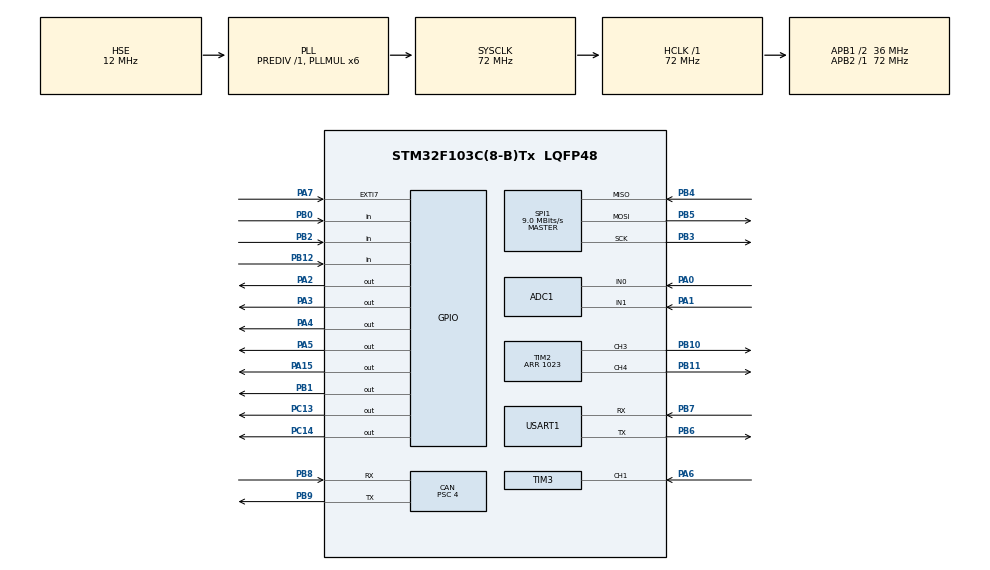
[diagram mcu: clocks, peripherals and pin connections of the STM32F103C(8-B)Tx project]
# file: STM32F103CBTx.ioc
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ADC1.Channel-0\#ChannelRegularConversion=ADC_CHANNEL_0
ADC1.Channel-1\#ChannelRegularConversion=ADC_CHANNEL_1
ADC1.ContinuousConvMode=ENABLE
ADC1.NbrOfConversion=2
ADC1.NbrOfConversionFlag=1
ADC1.Rank-0\#ChannelRegularConversion=1
ADC1.Rank-1\#ChannelRegularConversion=2
ADC1.SamplingTime-0\#ChannelRegularConversion=ADC_SAMPLETIME_239CYCLES_5
ADC1.SamplingTime-1\#ChannelRegularConversion=ADC_SAMPLETIME_1CYCLE_5
ADC1.master=1
CAN.AWUM=ENABLE
CAN.BS1=CAN_BS1_5TQ
CAN.BS2=CAN_BS2_3TQ
CAN.CalculateBaudRate=1000000
CAN.CalculateTimeBit=1000
CAN.CalculateTimeQuantum=111.11111111111111
CAN.Prescaler=4
Dma.ADC1.0.Direction=DMA_PERIPH_TO_MEMORY
Dma.ADC1.0.Instance=DMA1_Channel1
Dma.ADC1.0.MemDataAlignment=DMA_MDATAALIGN_HALFWORD
Dma.ADC1.0.MemInc=DMA_MINC_ENABLE
Dma.ADC1.0.Mode=DMA_CIRCULAR
Dma.ADC1.0.PeriphDataAlignment=DMA_PDATAALIGN_HALFWORD
Dma.ADC1.0.PeriphInc=DMA_PINC_DISABLE
Dma.ADC1.0.Priority=DMA_PRIORITY_VERY_HIGH
Dma.Request0=ADC1
Dma.Request1=USART1_RX
Dma.Request2=USART1_TX
Dma.USART1_RX.1.Direction=DMA_PERIPH_TO_MEMORY
Dma.USART1_RX.1.Instance=DMA1_Channel5
Dma.USART1_RX.1.MemDataAlignment=DMA_MDATAALIGN_BYTE
Dma.USART1_RX.1.MemInc=DMA_MINC_ENABLE
Dma.USART1_RX.1.Mode=DMA_NORMAL
Dma.USART1_RX.1.PeriphDataAlignment=DMA_PDATAALIGN_BYTE
Dma.USART1_RX.1.PeriphInc=DMA_PINC_DISABLE
Dma.USART1_RX.1.Priority=DMA_PRIORITY_MEDIUM
Dma.USART1_TX.2.Direction=DMA_MEMORY_TO_PERIPH
Dma.USART1_TX.2.Instance=DMA1_Channel4
Dma.USART1_TX.2.MemDataAlignment=DMA_MDATAALIGN_BYTE
Dma.USART1_TX.2.MemInc=DMA_MINC_ENABLE
Dma.USART1_TX.2.Mode=DMA_NORMAL
Dma.USART1_TX.2.PeriphDataAlignment=DMA_PDATAALIGN_BYTE
Dma.USART1_TX.2.PeriphInc=DMA_PINC_DISABLE
Dma.USART1_TX.2.Priority=DMA_PRIORITY_MEDIUM
Mcu.Family=STM32F1
Mcu.Name=STM32F103C(8-B)Tx
Mcu.Package=LQFP48
NVIC.CAN1_RX1_IRQn=true\:3\:0\:true\:false\:true\:true\:true\:true
NVIC.CAN1_SCE_IRQn=true\:3\:0\:true\:false\:true\:true\:true\:true
NVIC.DMA1_Channel1_IRQn=true\:0\:0\:false\:false\:true\:false\:true\:true
NVIC.DMA1_Channel4_IRQn=true\:3\:0\:true\:false\:true\:false\:true\:true
NVIC.DMA1_Channel5_IRQn=true\:3\:0\:true\:false\:true\:false\:true\:true
NVIC.EXTI9_5_IRQn=true\:0\:0\:false\:false\:true\:true\:true\:true
NVIC.PriorityGroup=NVIC_PRIORITYGROUP_4
NVIC.TIM1_UP_IRQn=true\:5\:0\:true\:false\:true\:true\:true\:true
NVIC.TIM3_IRQn=true\:0\:0\:false\:false\:true\:true\:true\:true
NVIC.TIM4_IRQn=true\:0\:0\:false\:false\:true\:true\:true\:true
NVIC.USART1_IRQn=true\:3\:0\:true\:false\:true\:true\:true\:true
NVIC.USB_HP_CAN1_TX_IRQn=true\:3\:0\:true\:false\:true\:true\:true\:true
NVIC.USB_LP_CAN1_RX0_IRQn=true\:3\:0\:true\:false\:true\:true\:true\:true
PA0-WKUP.Signal=ADCx_IN0
PA1.Signal=ADCx_IN1
PA15.Signal=GPIO_Output
PA2.GPIO_Speed=GPIO_SPEED_FREQ_HIGH
PA2.Signal=GPIO_Output
PA3.GPIO_Speed=GPIO_SPEED_FREQ_HIGH
PA3.Signal=GPIO_Output
PA4.GPIO_Speed=GPIO_SPEED_FREQ_HIGH
PA4.Signal=GPIO_Output
PA5.GPIO_Speed=GPIO_SPEED_FREQ_HIGH
PA5.Signal=GPIO_Output
PA6.Signal=S_TIM3_CH1
PA7.GPIO_ModeDefaultEXTI=GPIO_MODE_IT_RISING_FALLING
PA7.Signal=GPXTI7
PB0.Signal=GPIO_Input
PB1.Signal=GPIO_Output
PB10.GPIO_Speed=GPIO_SPEED_FREQ_HIGH
PB10.Signal=S_TIM2_CH3
PB11.GPIO_Speed=GPIO_SPEED_FREQ_HIGH
PB11.Signal=S_TIM2_CH4
PB12.GPIO_PuPd=GPIO_PULLUP
PB12.Signal=GPIO_Input
PB2.GPIO_PuPd=GPIO_PULLUP
PB2.Signal=GPIO_Input
PB3.Mode=Full_Duplex_Master
PB3.Signal=SPI1_SCK
PB4.Mode=Full_Duplex_Master
PB4.Signal=SPI1_MISO
PB5.Mode=Full_Duplex_Master
PB5.Signal=SPI1_MOSI
PB6.Mode=Asynchronous
PB6.Signal=USART1_TX
PB7.Mode=Asynchronous
PB7.Signal=USART1_RX
PB8.Mode=CAN_Activate
PB8.Signal=CAN_RX
PB9.Mode=CAN_Activate
PB9.Signal=CAN_TX
PC13-TAMPER-RTC.Signal=GPIO_Output
PC14-OSC32_IN.Signal=GPIO_Output
PD0-OSC_IN.Mode=HSE-External-Oscillator
PD0-OSC_IN.Signal=RCC_OSC_IN
PD1-OSC_OUT.Mode=HSE-External-Oscillator
PD1-OSC_OUT.Signal=RCC_OSC_OUT
ProjectManager.HeapSize=0x200
ProjectManager.StackSize=0x400
ProjectManager.TargetToolchain=STM32CubeIDE
RCC.ADCPresc=RCC_ADCPCLK2_DIV6
RCC.AHBFreq_Value=72000000
RCC.APB1CLKDivider=RCC_HCLK_DIV2
RCC.APB1Freq_Value=36000000
RCC.APB1TimFreq_Value=72000000
RCC.APB2Freq_Value=72000000
RCC.APB2TimFreq_Value=72000000
RCC.HCLKFreq_Value=72000000
RCC.HSE_VALUE=12000000
RCC.PLLMUL=RCC_PLL_MUL6
RCC.PLLSourceVirtual=RCC_PLLSOURCE_HSE
RCC.SYSCLKFreq_VALUE=72000000
RCC.SYSCLKSource=RCC_SYSCLKSOURCE_PLLCLK
RCC.USBFreq_Value=72000000
SH.ADCx_IN0.0=ADC1_IN0,IN0
SH.ADCx_IN1.0=ADC1_IN1,IN1
SH.S_TIM2_CH3.0=TIM2_CH3,PWM Generation3 CH3
SH.S_TIM2_CH4.0=TIM2_CH4,PWM Generation4 CH4
SH.S_TIM3_CH1.0=TIM3_CH1,TriggerSource_TI1FP1
SH.S_TIM3_CH1.1=TIM3_CH1,Input_Capture1_from_TI1
SPI1.BaudRatePrescaler=SPI_BAUDRATEPRESCALER_8
SPI1.CLKPhase=SPI_PHASE_2EDGE
SPI1.CLKPolarity=SPI_POLARITY_HIGH
SPI1.CRCCalculation=SPI_CRCCALCULATION_DISABLE
SPI1.CalculateBaudRate=9.0 MBits/s
SPI1.DataSize=SPI_DATASIZE_16BIT
SPI1.Direction=SPI_DIRECTION_2LINES
SPI1.Mode=SPI_MODE_MASTER
SPI1.VirtualType=VM_MASTER
TIM1.AutoReloadPreload=TIM_AUTORELOAD_PRELOAD_ENABLE
TIM1.ClockDivision=TIM_CLOCKDIVISION_DIV1
TIM1.Period=9999
TIM1.Prescaler=71
TIM2.Channel-PWM\ Generation3\ CH3=TIM_CHANNEL_3
TIM2.Channel-PWM\ Generation4\ CH4=TIM_CHANNEL_4
TIM2.ClockDivision=TIM_CLOCKDIVISION_DIV1
TIM2.Period=1023
TIM3.Channel-Input_Capture1_from_TI1=TIM_CHANNEL_1
TIM3.ClockDivision=TIM_CLOCKDIVISION_DIV1
TIM3.ICPrescaler-Input_Capture1_from_TI1=TIM_ICPSC_DIV2
TIM3.Prescaler=71
TIM4.AutoReloadPreload=TIM_AUTORELOAD_PRELOAD_ENABLE
TIM4.ClockDivision=TIM_CLOCKDIVISION_DIV1
TIM4.Period=49
TIM4.Prescaler=71
USART1.VirtualMode=VM_ASYNC
VP_SYS_VS_ND.Mode=No_Debug
VP_TIM1_VS_ClockSourceINT.Mode=Internal
VP_TIM3_VS_ControllerModeReset.Mode=Reset Mode
VP_TIM4_VS_ClockSourceINT.Mode=Internal
board=custom

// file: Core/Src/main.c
/* USER CODE BEGIN Header */
/**
  ******************************************************************************
  * @file           : main.c
  * @brief          : Main program body
  ******************************************************************************
  * @attention
  *
  * Copyright (c) 2024 STMicroelectronics.
  * All rights reserved.
  *
  * This software is licensed under terms that can be found in the LICENSE file
  * in the root directory of this software component.
  * If no LICENSE file comes with this software, it is provided AS-IS.
  *
  ******************************************************************************
  */
/* USER CODE END Header */
#include "main.h"

/* USER CODE BEGIN Includes */
#include "common_inc.h"
#include "configurations.h"
/* USER CODE END Includes */

/* USER CODE BEGIN PD */
uint16_t whole_adc_data[2][12];
/* USER CODE END PD */

 ADC_HandleTypeDef hadc1;
DMA_HandleTypeDef hdma_adc1;

CAN_HandleTypeDef hcan;

SPI_HandleTypeDef hspi1;

TIM_HandleTypeDef htim1;
TIM_HandleTypeDef htim2;
TIM_HandleTypeDef htim3;
TIM_HandleTypeDef htim4;

UART_HandleTypeDef huart1;
DMA_HandleTypeDef hdma_usart1_rx;
DMA_HandleTypeDef hdma_usart1_tx;

/* USER CODE BEGIN PV */
CAN_TxHeaderTypeDef TxHeader;
CAN_RxHeaderTypeDef RxHeader;
uint8_t TxData[8];
uint8_t RxData[8];
uint32_t TxMailbox;
/* USER CODE END PV */

void SystemClock_Config(void);
static void MX_GPIO_Init(void);
static void MX_DMA_Init(void);
static void MX_ADC1_Init(void);
static void MX_CAN_Init(void);
static void MX_SPI1_Init(void);
static void MX_TIM1_Init(void);
static void MX_TIM2_Init(void);
static void MX_TIM3_Init(void);
static void MX_TIM4_Init(void);
static void MX_USART1_UART_Init(void);

/* USER CODE BEGIN 0 */
void CAN_Send(CAN_TxHeaderTypeDef* pHeader, uint8_t* data)
{
    if (HAL_CAN_AddTxMessage(&hcan, pHeader, data, &TxMailbox) != HAL_OK)
    {
        Error_Handler();
    }
}

void HAL_CAN_RxFifo0MsgPendingCallback(CAN_HandleTypeDef* CanHandle)
{
    /* Get RX message */
    if (HAL_CAN_GetRxMessage(CanHandle, CAN_RX_FIFO0, &RxHeader, RxData) != HAL_OK)
    {
        /* Reception Error */
        Error_Handler();
    }

    uint8_t id = (RxHeader.StdId >> 7); // 4Bits ID & 7Bits Msg
    uint8_t cmd = RxHeader.StdId & 0x7F; // 4Bits ID & 7Bits Msg
    if (id == 0 || id == boardConfig.canNodeId)
    {
        OnCanCmd(cmd, RxData, RxHeader.DLC);
    }
}
/* USER CODE END 0 */

int main(void)
{

  /* MCU Configuration--------------------------------------------------------*/

  /* Reset of all peripherals, Initializes the Flash interface and the Systick. */
  HAL_Init();

  /* Configure the system clock */
  SystemClock_Config();

  /* Initialize all configured peripherals */
  MX_GPIO_Init();
  MX_DMA_Init();
  MX_ADC1_Init();
  MX_CAN_Init();
  MX_SPI1_Init();
  MX_TIM1_Init();
  MX_TIM2_Init();
  MX_TIM3_Init();
  MX_TIM4_Init();
  MX_USART1_UART_Init();
  /* USER CODE BEGIN 2 */
  Main();
  /* USER CODE END 2 */

  /* Infinite loop */
  while (1)
  {

  }
}

void SystemClock_Config(void)
{
  RCC_OscInitTypeDef RCC_OscInitStruct = {0};
  RCC_ClkInitTypeDef RCC_ClkInitStruct = {0};
  RCC_PeriphCLKInitTypeDef PeriphClkInit = {0};

  /** Initializes the RCC Oscillators according to the specified parameters
  * in the RCC_OscInitTypeDef structure.
  */
  RCC_OscInitStruct.OscillatorType = RCC_OSCILLATORTYPE_HSE;
  RCC_OscInitStruct.HSEState = RCC_HSE_ON;
  RCC_OscInitStruct.HSEPredivValue = RCC_HSE_PREDIV_DIV1;
  RCC_OscInitStruct.HSIState = RCC_HSI_ON;
  RCC_OscInitStruct.PLL.PLLState = RCC_PLL_ON;
  RCC_OscInitStruct.PLL.PLLSource = RCC_PLLSOURCE_HSE;
  RCC_OscInitStruct.PLL.PLLMUL = RCC_PLL_MUL6;
  if (HAL_RCC_OscConfig(&RCC_OscInitStruct) != HAL_OK)
  {
    Error_Handler();
  }

  /** Initializes the CPU, AHB and APB buses clocks
  */
  RCC_ClkInitStruct.ClockType = RCC_CLOCKTYPE_HCLK|RCC_CLOCKTYPE_SYSCLK
                              |RCC_CLOCKTYPE_PCLK1|RCC_CLOCKTYPE_PCLK2;
  RCC_ClkInitStruct.SYSCLKSource = RCC_SYSCLKSOURCE_PLLCLK;
  RCC_ClkInitStruct.AHBCLKDivider = RCC_SYSCLK_DIV1;
  RCC_ClkInitStruct.APB1CLKDivider = RCC_HCLK_DIV2;
  RCC_ClkInitStruct.APB2CLKDivider = RCC_HCLK_DIV1;

  if (HAL_RCC_ClockConfig(&RCC_ClkInitStruct, FLASH_LATENCY_2) != HAL_OK)
  {
    Error_Handler();
  }
  PeriphClkInit.PeriphClockSelection = RCC_PERIPHCLK_ADC;
  PeriphClkInit.AdcClockSelection = RCC_ADCPCLK2_DIV6;
  if (HAL_RCCEx_PeriphCLKConfig(&PeriphClkInit) != HAL_OK)
  {
    Error_Handler();
  }
}

static void MX_ADC1_Init(void)
{

  ADC_ChannelConfTypeDef sConfig = {0};

  /** Common config
  */
  hadc1.Instance = ADC1;
  hadc1.Init.ScanConvMode = ADC_SCAN_ENABLE;
  hadc1.Init.ContinuousConvMode = ENABLE;
  hadc1.Init.DiscontinuousConvMode = DISABLE;
  hadc1.Init.ExternalTrigConv = ADC_SOFTWARE_START;
  hadc1.Init.DataAlign = ADC_DATAALIGN_RIGHT;
  hadc1.Init.NbrOfConversion = 2;
  if (HAL_ADC_Init(&hadc1) != HAL_OK)
  {
    Error_Handler();
  }

  /** Configure Regular Channel
  */
  sConfig.Channel = ADC_CHANNEL_0;
  sConfig.Rank = ADC_REGULAR_RANK_1;
  sConfig.SamplingTime = ADC_SAMPLETIME_239CYCLES_5;
  if (HAL_ADC_ConfigChannel(&hadc1, &sConfig) != HAL_OK)
  {
    Error_Handler();
  }

  /** Configure Regular Channel
  */
  sConfig.Channel = ADC_CHANNEL_1;
  sConfig.Rank = ADC_REGULAR_RANK_2;
  sConfig.SamplingTime = ADC_SAMPLETIME_1CYCLE_5;
  if (HAL_ADC_ConfigChannel(&hadc1, &sConfig) != HAL_OK)
  {
    Error_Handler();
  }
  /* USER CODE BEGIN ADC1_Init 2 */
  HAL_ADCEx_Calibration_Start(&hadc1);
  HAL_ADC_Start_DMA(&hadc1, (uint32_t*)&whole_adc_data[0][0], 2);
  /* USER CODE END ADC1_Init 2 */

}

static void MX_CAN_Init(void)
{

  hcan.Instance = CAN1;
  hcan.Init.Prescaler = 4;
  hcan.Init.Mode = CAN_MODE_NORMAL;
  hcan.Init.SyncJumpWidth = CAN_SJW_1TQ;
  hcan.Init.TimeSeg1 = CAN_BS1_5TQ;
  hcan.Init.TimeSeg2 = CAN_BS2_3TQ;
  hcan.Init.TimeTriggeredMode = DISABLE;
  hcan.Init.AutoBusOff = DISABLE;
  hcan.Init.AutoWakeUp = ENABLE;
  hcan.Init.AutoRetransmission = DISABLE;
  hcan.Init.ReceiveFifoLocked = DISABLE;
  hcan.Init.TransmitFifoPriority = DISABLE;
  if (HAL_CAN_Init(&hcan) != HAL_OK)
  {
    Error_Handler();
  }
  /* USER CODE BEGIN CAN_Init 2 */
  CAN_FilterTypeDef sFilterConfig;
  //filter one (stack light blink)
  sFilterConfig.FilterBank = 0;
  sFilterConfig.FilterMode = CAN_FILTERMODE_IDMASK;
  sFilterConfig.FilterScale = CAN_FILTERSCALE_32BIT;
  sFilterConfig.FilterIdHigh = 0x0000;
  sFilterConfig.FilterIdLow = 0x0000;
  sFilterConfig.FilterMaskIdHigh = 0x0000;
  sFilterConfig.FilterMaskIdLow = 0x0000;
  sFilterConfig.FilterFIFOAssignment = CAN_RX_FIFO0;
  sFilterConfig.FilterActivation = ENABLE;
  sFilterConfig.SlaveStartFilterBank = 14;
  if (HAL_CAN_ConfigFilter(&hcan, &sFilterConfig) != HAL_OK)
  {
      /* Filter configuration Error */
      Error_Handler();
  }

  HAL_CAN_Start(&hcan); //start CAN

  HAL_CAN_ActivateNotification(&hcan,
                               CAN_IT_TX_MAILBOX_EMPTY |
                               CAN_IT_RX_FIFO0_MSG_PENDING | CAN_IT_RX_FIFO1_MSG_PENDING |
                               /* we probably only want this */
                               CAN_IT_RX_FIFO0_FULL | CAN_IT_RX_FIFO1_FULL |
                               CAN_IT_RX_FIFO0_OVERRUN | CAN_IT_RX_FIFO1_OVERRUN |
                               CAN_IT_WAKEUP | CAN_IT_SLEEP_ACK |
                               CAN_IT_ERROR_WARNING | CAN_IT_ERROR_PASSIVE |
                               CAN_IT_BUSOFF | CAN_IT_LAST_ERROR_CODE |
                               CAN_IT_ERROR);

  /* Configure Transmission process */
  TxHeader.StdId = boardConfig.canNodeId;
  TxHeader.ExtId = 0x00;
  TxHeader.RTR = CAN_RTR_DATA;
  TxHeader.IDE = CAN_ID_STD;
  TxHeader.DLC = 8;
  TxHeader.TransmitGlobalTime = DISABLE;
  /* USER CODE END CAN_Init 2 */

}

static void MX_SPI1_Init(void)
{

  /* SPI1 parameter configuration*/
  hspi1.Instance = SPI1;
  hspi1.Init.Mode = SPI_MODE_MASTER;
  hspi1.Init.Direction = SPI_DIRECTION_2LINES;
  hspi1.Init.DataSize = SPI_DATASIZE_16BIT;
  hspi1.Init.CLKPolarity = SPI_POLARITY_HIGH;
  hspi1.Init.CLKPhase = SPI_PHASE_2EDGE;
  hspi1.Init.NSS = SPI_NSS_SOFT;
  hspi1.Init.BaudRatePrescaler = SPI_BAUDRATEPRESCALER_8;
  hspi1.Init.FirstBit = SPI_FIRSTBIT_MSB;
  hspi1.Init.TIMode = SPI_TIMODE_DISABLE;
  hspi1.Init.CRCCalculation = SPI_CRCCALCULATION_DISABLE;
  hspi1.Init.CRCPolynomial = 10;
  if (HAL_SPI_Init(&hspi1) != HAL_OK)
  {
    Error_Handler();
  }

}

static void MX_TIM1_Init(void)
{

  TIM_ClockConfigTypeDef sClockSourceConfig = {0};
  TIM_MasterConfigTypeDef sMasterConfig = {0};

  htim1.Instance = TIM1;
  htim1.Init.Prescaler = 71;
  htim1.Init.CounterMode = TIM_COUNTERMODE_UP;
  htim1.Init.Period = 9999;
  htim1.Init.ClockDivision = TIM_CLOCKDIVISION_DIV1;
  htim1.Init.RepetitionCounter = 0;
  htim1.Init.AutoReloadPreload = TIM_AUTORELOAD_PRELOAD_ENABLE;
  if (HAL_TIM_Base_Init(&htim1) != HAL_OK)
  {
    Error_Handler();
  }
  sClockSourceConfig.ClockSource = TIM_CLOCKSOURCE_INTERNAL;
  if (HAL_TIM_ConfigClockSource(&htim1, &sClockSourceConfig) != HAL_OK)
  {
    Error_Handler();
  }
  sMasterConfig.MasterOutputTrigger = TIM_TRGO_RESET;
  sMasterConfig.MasterSlaveMode = TIM_MASTERSLAVEMODE_DISABLE;
  if (HAL_TIMEx_MasterConfigSynchronization(&htim1, &sMasterConfig) != HAL_OK)
  {
    Error_Handler();
  }

}

static void MX_TIM2_Init(void)
{

  TIM_MasterConfigTypeDef sMasterConfig = {0};
  TIM_OC_InitTypeDef sConfigOC = {0};

  htim2.Instance = TIM2;
  htim2.Init.Prescaler = 0;
  htim2.Init.CounterMode = TIM_COUNTERMODE_UP;
  htim2.Init.Period = 1023;
  htim2.Init.ClockDivision = TIM_CLOCKDIVISION_DIV1;
  htim2.Init.AutoReloadPreload = TIM_AUTORELOAD_PRELOAD_DISABLE;
  if (HAL_TIM_PWM_Init(&htim2) != HAL_OK)
  {
    Error_Handler();
  }
  sMasterConfig.MasterOutputTrigger = TIM_TRGO_RESET;
  sMasterConfig.MasterSlaveMode = TIM_MASTERSLAVEMODE_DISABLE;
  if (HAL_TIMEx_MasterConfigSynchronization(&htim2, &sMasterConfig) != HAL_OK)
  {
    Error_Handler();
  }
  sConfigOC.OCMode = TIM_OCMODE_PWM1;
  sConfigOC.Pulse = 0;
  sConfigOC.OCPolarity = TIM_OCPOLARITY_HIGH;
  sConfigOC.OCFastMode = TIM_OCFAST_DISABLE;
  if (HAL_TIM_PWM_ConfigChannel(&htim2, &sConfigOC, TIM_CHANNEL_3) != HAL_OK)
  {
    Error_Handler();
  }
  if (HAL_TIM_PWM_ConfigChannel(&htim2, &sConfigOC, TIM_CHANNEL_4) != HAL_OK)
  {
    Error_Handler();
  }
  /* USER CODE BEGIN TIM2_Init 2 */
  HAL_TIM_PWM_Start(&htim2, TIM_CHANNEL_3);
  HAL_TIM_PWM_Start(&htim2, TIM_CHANNEL_4);
  /* USER CODE END TIM2_Init 2 */
  HAL_TIM_MspPostInit(&htim2);

}

static void MX_TIM3_Init(void)
{

  TIM_SlaveConfigTypeDef sSlaveConfig = {0};
  TIM_MasterConfigTypeDef sMasterConfig = {0};
  TIM_IC_InitTypeDef sConfigIC = {0};

  htim3.Instance = TIM3;
  htim3.Init.Prescaler = 71;
  htim3.Init.CounterMode = TIM_COUNTERMODE_UP;
  htim3.Init.Period = 65535;
  htim3.Init.ClockDivision = TIM_CLOCKDIVISION_DIV1;
  htim3.Init.AutoReloadPreload = TIM_AUTORELOAD_PRELOAD_DISABLE;
  if (HAL_TIM_Base_Init(&htim3) != HAL_OK)
  {
    Error_Handler();
  }
  if (HAL_TIM_IC_Init(&htim3) != HAL_OK)
  {
    Error_Handler();
  }
  sSlaveConfig.SlaveMode = TIM_SLAVEMODE_RESET;
  sSlaveConfig.InputTrigger = TIM_TS_TI1FP1;
  sSlaveConfig.TriggerPolarity = TIM_INPUTCHANNELPOLARITY_RISING;
  sSlaveConfig.TriggerFilter = 0;
  if (HAL_TIM_SlaveConfigSynchro(&htim3, &sSlaveConfig) != HAL_OK)
  {
    Error_Handler();
  }
  sMasterConfig.MasterOutputTrigger = TIM_TRGO_RESET;
  sMasterConfig.MasterSlaveMode = TIM_MASTERSLAVEMODE_DISABLE;
  if (HAL_TIMEx_MasterConfigSynchronization(&htim3, &sMasterConfig) != HAL_OK)
  {
    Error_Handler();
  }
  sConfigIC.ICPolarity = TIM_INPUTCHANNELPOLARITY_RISING;
  sConfigIC.ICSelection = TIM_ICSELECTION_DIRECTTI;
  sConfigIC.ICPrescaler = TIM_ICPSC_DIV2;
  sConfigIC.ICFilter = 0;
  if (HAL_TIM_IC_ConfigChannel(&htim3, &sConfigIC, TIM_CHANNEL_1) != HAL_OK)
  {
    Error_Handler();
  }

}

static void MX_TIM4_Init(void)
{

  TIM_ClockConfigTypeDef sClockSourceConfig = {0};
  TIM_MasterConfigTypeDef sMasterConfig = {0};

  htim4.Instance = TIM4;
  htim4.Init.Prescaler = 71;
  htim4.Init.CounterMode = TIM_COUNTERMODE_UP;
  htim4.Init.Period = 49;
  htim4.Init.ClockDivision = TIM_CLOCKDIVISION_DIV1;
  htim4.Init.AutoReloadPreload = TIM_AUTORELOAD_PRELOAD_ENABLE;
  if (HAL_TIM_Base_Init(&htim4) != HAL_OK)
  {
    Error_Handler();
  }
  sClockSourceConfig.ClockSource = TIM_CLOCKSOURCE_INTERNAL;
  if (HAL_TIM_ConfigClockSource(&htim4, &sClockSourceConfig) != HAL_OK)
  {
    Error_Handler();
  }
  sMasterConfig.MasterOutputTrigger = TIM_TRGO_RESET;
  sMasterConfig.MasterSlaveMode = TIM_MASTERSLAVEMODE_DISABLE;
  if (HAL_TIMEx_MasterConfigSynchronization(&htim4, &sMasterConfig) != HAL_OK)
  {
    Error_Handler();
  }

}

static void MX_USART1_UART_Init(void)
{

  huart1.Instance = USART1;
  huart1.Init.BaudRate = 115200;
  huart1.Init.WordLength = UART_WORDLENGTH_8B;
  huart1.Init.StopBits = UART_STOPBITS_1;
  huart1.Init.Parity = UART_PARITY_NONE;
  huart1.Init.Mode = UART_MODE_TX_RX;
  huart1.Init.HwFlowCtl = UART_HWCONTROL_NONE;
  huart1.Init.OverSampling = UART_OVERSAMPLING_16;
  if (HAL_UART_Init(&huart1) != HAL_OK)
  {
    Error_Handler();
  }
  /* USER CODE BEGIN USART1_Init 2 */
  __HAL_UART_ENABLE_IT(&huart1, UART_IT_IDLE);
  RetargetInit(&huart1);
  Uart_SetRxCpltCallBack(OnUartCmd);

  HAL_UART_Receive_DMA(&huart1, rx_buffer, BUFFER_SIZE);
  /* USER CODE END USART1_Init 2 */

}

static void MX_DMA_Init(void)
{

  /* DMA controller clock enable */
  __HAL_RCC_DMA1_CLK_ENABLE();

  /* DMA interrupt init */
  /* DMA1_Channel1_IRQn interrupt configuration */
  HAL_NVIC_SetPriority(DMA1_Channel1_IRQn, 0, 0);
  HAL_NVIC_EnableIRQ(DMA1_Channel1_IRQn);
  /* DMA1_Channel4_IRQn interrupt configuration */
  HAL_NVIC_SetPriority(DMA1_Channel4_IRQn, 3, 0);
  HAL_NVIC_EnableIRQ(DMA1_Channel4_IRQn);
  /* DMA1_Channel5_IRQn interrupt configuration */
  HAL_NVIC_SetPriority(DMA1_Channel5_IRQn, 3, 0);
  HAL_NVIC_EnableIRQ(DMA1_Channel5_IRQn);

}

static void MX_GPIO_Init(void)
{
  GPIO_InitTypeDef GPIO_InitStruct = {0};

  /* GPIO Ports Clock Enable */
  __HAL_RCC_GPIOC_CLK_ENABLE();
  __HAL_RCC_GPIOD_CLK_ENABLE();
  __HAL_RCC_GPIOA_CLK_ENABLE();
  __HAL_RCC_GPIOB_CLK_ENABLE();

  /*Configure GPIO pin Output Level */
  HAL_GPIO_WritePin(GPIOC, LED1_Pin|LED2_Pin, GPIO_PIN_RESET);

  /*Configure GPIO pin Output Level */
  HAL_GPIO_WritePin(GPIOA, HW_ELEC_BM_Pin|HW_ELEC_BP_Pin|HW_ELEC_AM_Pin|HW_ELEC_AP_Pin, GPIO_PIN_RESET);

  /*Configure GPIO pin Output Level */
  HAL_GPIO_WritePin(SIGNAL_ALERT_GPIO_Port, SIGNAL_ALERT_Pin, GPIO_PIN_RESET);

  /*Configure GPIO pin Output Level */
  HAL_GPIO_WritePin(SPI1_CS_GPIO_Port, SPI1_CS_Pin, GPIO_PIN_SET);

  /*Configure GPIO pins : PC13 PC14 */
  GPIO_InitStruct.Pin = LED1_Pin|LED2_Pin;
  GPIO_InitStruct.Mode = GPIO_MODE_OUTPUT_PP;
  GPIO_InitStruct.Pull = GPIO_NOPULL;
  GPIO_InitStruct.Speed = GPIO_SPEED_FREQ_LOW;
  HAL_GPIO_Init(GPIOC, &GPIO_InitStruct);

  /*Configure GPIO pins : PA2 PA3 PA4 PA5 */
  GPIO_InitStruct.Pin = HW_ELEC_BM_Pin|HW_ELEC_BP_Pin|HW_ELEC_AM_Pin|HW_ELEC_AP_Pin;
  GPIO_InitStruct.Mode = GPIO_MODE_OUTPUT_PP;
  GPIO_InitStruct.Pull = GPIO_NOPULL;
  GPIO_InitStruct.Speed = GPIO_SPEED_FREQ_HIGH;
  HAL_GPIO_Init(GPIOA, &GPIO_InitStruct);

  /*Configure GPIO pin : PA7 */
  GPIO_InitStruct.Pin = SIGNAL_COUNT_DIR_Pin;
  GPIO_InitStruct.Mode = GPIO_MODE_IT_RISING_FALLING;
  GPIO_InitStruct.Pull = GPIO_NOPULL;
  HAL_GPIO_Init(SIGNAL_COUNT_DIR_GPIO_Port, &GPIO_InitStruct);

  /*Configure GPIO pin : PB0 */
  GPIO_InitStruct.Pin = SIGNAL_COUNT_EN_Pin;
  GPIO_InitStruct.Mode = GPIO_MODE_INPUT;
  GPIO_InitStruct.Pull = GPIO_NOPULL;
  HAL_GPIO_Init(SIGNAL_COUNT_EN_GPIO_Port, &GPIO_InitStruct);

  /*Configure GPIO pin : PB1 */
  GPIO_InitStruct.Pin = SIGNAL_ALERT_Pin;
  GPIO_InitStruct.Mode = GPIO_MODE_OUTPUT_PP;
  GPIO_InitStruct.Pull = GPIO_NOPULL;
  GPIO_InitStruct.Speed = GPIO_SPEED_FREQ_LOW;
  HAL_GPIO_Init(SIGNAL_ALERT_GPIO_Port, &GPIO_InitStruct);

  /*Configure GPIO pins : PB2 PB12 */
  GPIO_InitStruct.Pin = BUTTON2_Pin|BUTTON1_Pin;
  GPIO_InitStruct.Mode = GPIO_MODE_INPUT;
  GPIO_InitStruct.Pull = GPIO_PULLUP;
  HAL_GPIO_Init(GPIOB, &GPIO_InitStruct);

  /*Configure GPIO pin : PA15 */
  GPIO_InitStruct.Pin = SPI1_CS_Pin;
  GPIO_InitStruct.Mode = GPIO_MODE_OUTPUT_PP;
  GPIO_InitStruct.Pull = GPIO_NOPULL;
  GPIO_InitStruct.Speed = GPIO_SPEED_FREQ_LOW;
  HAL_GPIO_Init(SPI1_CS_GPIO_Port, &GPIO_InitStruct);

  /* EXTI interrupt init*/
  HAL_NVIC_SetPriority(EXTI9_5_IRQn, 0, 0);
  HAL_NVIC_EnableIRQ(EXTI9_5_IRQn);

}

void Error_Handler(void)
{
  __disable_irq();
  while (1)
  {
  }
}
